VERSION 5.7 ;
  NOWIREEXTENSIONATPIN ON ;
  DIVIDERCHAR "/" ;
  BUSBITCHARS "[]" ;
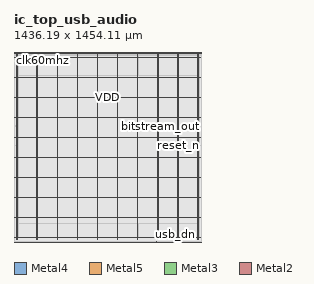
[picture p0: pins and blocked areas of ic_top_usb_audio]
MACRO ic_top_usb_audio
  CLASS BLOCK ;
  FOREIGN ic_top_usb_audio ;
  ORIGIN 0.000 0.000 ;
  SIZE 1436.190 BY 1454.110 ;
  PIN VDD
    DIRECTION INOUT ;
    USE POWER ;
    PORT
      LAYER Metal4 ;
        RECT 22.240 15.380 23.840 1435.020 ;
    END
    PORT
      LAYER Metal4 ;
        RECT 175.840 15.380 177.440 1435.020 ;
    END
    PORT
      LAYER Metal4 ;
        RECT 329.440 15.380 331.040 1435.020 ;
    END
    PORT
      LAYER Metal4 ;
        RECT 483.040 15.380 484.640 1435.020 ;
    END
    PORT
      LAYER Metal4 ;
        RECT 636.640 15.380 638.240 1435.020 ;
    END
    PORT
      LAYER Metal4 ;
        RECT 790.240 15.380 791.840 1435.020 ;
    END
    PORT
      LAYER Metal4 ;
        RECT 943.840 15.380 945.440 1435.020 ;
    END
    PORT
      LAYER Metal4 ;
        RECT 1097.440 15.380 1099.040 1435.020 ;
    END
    PORT
      LAYER Metal4 ;
        RECT 1251.040 15.380 1252.640 1435.020 ;
    END
    PORT
      LAYER Metal4 ;
        RECT 1404.640 15.380 1406.240 1435.020 ;
    END
    PORT
      LAYER Metal5 ;
        RECT 6.720 31.530 1429.120 33.130 ;
    END
    PORT
      LAYER Metal5 ;
        RECT 6.720 184.710 1429.120 186.310 ;
    END
    PORT
      LAYER Metal5 ;
        RECT 6.720 337.890 1429.120 339.490 ;
    END
    PORT
      LAYER Metal5 ;
        RECT 6.720 491.070 1429.120 492.670 ;
    END
    PORT
      LAYER Metal5 ;
        RECT 6.720 644.250 1429.120 645.850 ;
    END
    PORT
      LAYER Metal5 ;
        RECT 6.720 797.430 1429.120 799.030 ;
    END
    PORT
      LAYER Metal5 ;
        RECT 6.720 950.610 1429.120 952.210 ;
    END
    PORT
      LAYER Metal5 ;
        RECT 6.720 1103.790 1429.120 1105.390 ;
    END
    PORT
      LAYER Metal5 ;
        RECT 6.720 1256.970 1429.120 1258.570 ;
    END
    PORT
      LAYER Metal5 ;
        RECT 6.720 1410.150 1429.120 1411.750 ;
    END
  END VDD
  PIN VSS
    DIRECTION INOUT ;
    USE GROUND ;
    PORT
      LAYER Metal4 ;
        RECT 25.540 15.380 27.140 1435.020 ;
    END
    PORT
      LAYER Metal4 ;
        RECT 179.140 15.380 180.740 1435.020 ;
    END
    PORT
      LAYER Metal4 ;
        RECT 332.740 15.380 334.340 1435.020 ;
    END
    PORT
      LAYER Metal4 ;
        RECT 486.340 15.380 487.940 1435.020 ;
    END
    PORT
      LAYER Metal4 ;
        RECT 639.940 15.380 641.540 1435.020 ;
    END
    PORT
      LAYER Metal4 ;
        RECT 793.540 15.380 795.140 1435.020 ;
    END
    PORT
      LAYER Metal4 ;
        RECT 947.140 15.380 948.740 1435.020 ;
    END
    PORT
      LAYER Metal4 ;
        RECT 1100.740 15.380 1102.340 1435.020 ;
    END
    PORT
      LAYER Metal4 ;
        RECT 1254.340 15.380 1255.940 1435.020 ;
    END
    PORT
      LAYER Metal4 ;
        RECT 1407.940 15.380 1409.540 1435.020 ;
    END
    PORT
      LAYER Metal5 ;
        RECT 6.720 34.830 1429.120 36.430 ;
    END
    PORT
      LAYER Metal5 ;
        RECT 6.720 188.010 1429.120 189.610 ;
    END
    PORT
      LAYER Metal5 ;
        RECT 6.720 341.190 1429.120 342.790 ;
    END
    PORT
      LAYER Metal5 ;
        RECT 6.720 494.370 1429.120 495.970 ;
    END
    PORT
      LAYER Metal5 ;
        RECT 6.720 647.550 1429.120 649.150 ;
    END
    PORT
      LAYER Metal5 ;
        RECT 6.720 800.730 1429.120 802.330 ;
    END
    PORT
      LAYER Metal5 ;
        RECT 6.720 953.910 1429.120 955.510 ;
    END
    PORT
      LAYER Metal5 ;
        RECT 6.720 1107.090 1429.120 1108.690 ;
    END
    PORT
      LAYER Metal5 ;
        RECT 6.720 1260.270 1429.120 1261.870 ;
    END
    PORT
      LAYER Metal5 ;
        RECT 6.720 1413.450 1429.120 1415.050 ;
    END
  END VSS
  PIN bitstream_out
    DIRECTION OUTPUT ;
    USE SIGNAL ;
    ANTENNADIFFAREA 0.897600 ;
    PORT
      LAYER Metal3 ;
        RECT 1435.630 887.040 1436.190 887.600 ;
    END
  END bitstream_out
  PIN clk60mhz
    DIRECTION INPUT ;
    USE SIGNAL ;
    ANTENNAGATEAREA 0.396000 ;
    PORT
      LAYER Metal3 ;
        RECT 0.000 1425.760 0.560 1426.320 ;
    END
  END clk60mhz
  PIN reset_n
    DIRECTION INPUT ;
    USE SIGNAL ;
    ANTENNAGATEAREA 0.396000 ;
    PORT
      LAYER Metal3 ;
        RECT 1435.630 738.080 1436.190 738.640 ;
    END
  END reset_n
  PIN usb_dn
    DIRECTION INOUT ;
    USE SIGNAL ;
    ANTENNADIFFAREA 2.080400 ;
    PORT
      LAYER Metal2 ;
        RECT 1232.000 0.000 1232.560 0.560 ;
    END
  END usb_dn
  PIN usb_dp
    DIRECTION INOUT ;
    USE SIGNAL ;
    ANTENNADIFFAREA 2.080400 ;
    PORT
      LAYER Metal2 ;
        RECT 1223.040 0.000 1223.600 0.560 ;
    END
  END usb_dp
  PIN usb_dp_pull
    DIRECTION OUTPUT ;
    USE SIGNAL ;
    ANTENNADIFFAREA 0.897600 ;
    PORT
      LAYER Metal2 ;
        RECT 1088.640 0.000 1089.200 0.560 ;
    END
  END usb_dp_pull
  OBS
      LAYER Nwell ;
        RECT 6.290 15.250 1429.550 1435.150 ;
      LAYER Metal1 ;
        RECT 6.720 15.380 1429.120 1435.020 ;
      LAYER Metal2 ;
        RECT 9.100 0.860 1427.300 1434.910 ;
        RECT 9.100 0.090 1088.340 0.860 ;
        RECT 1089.500 0.090 1222.740 0.860 ;
        RECT 1223.900 0.090 1231.700 0.860 ;
        RECT 1232.860 0.090 1427.300 0.860 ;
      LAYER Metal3 ;
        RECT 0.560 1426.620 1435.630 1434.860 ;
        RECT 0.860 1425.460 1435.630 1426.620 ;
        RECT 0.560 887.900 1435.630 1425.460 ;
        RECT 0.560 886.740 1435.330 887.900 ;
        RECT 0.560 738.940 1435.630 886.740 ;
        RECT 0.560 737.780 1435.330 738.940 ;
        RECT 0.560 0.140 1435.630 737.780 ;
      LAYER Metal4 ;
        RECT 33.180 37.050 175.540 1429.030 ;
        RECT 177.740 37.050 178.840 1429.030 ;
        RECT 181.040 37.050 329.140 1429.030 ;
        RECT 331.340 37.050 332.440 1429.030 ;
        RECT 334.640 37.050 482.740 1429.030 ;
        RECT 484.940 37.050 486.040 1429.030 ;
        RECT 488.240 37.050 636.340 1429.030 ;
        RECT 638.540 37.050 639.640 1429.030 ;
        RECT 641.840 37.050 789.940 1429.030 ;
        RECT 792.140 37.050 793.240 1429.030 ;
        RECT 795.440 37.050 943.540 1429.030 ;
        RECT 945.740 37.050 946.840 1429.030 ;
        RECT 949.040 37.050 1097.140 1429.030 ;
        RECT 1099.340 37.050 1100.440 1429.030 ;
        RECT 1102.640 37.050 1250.740 1429.030 ;
        RECT 1252.940 37.050 1254.040 1429.030 ;
        RECT 1256.240 37.050 1404.340 1429.030 ;
        RECT 1406.540 37.050 1407.640 1429.030 ;
        RECT 1409.840 37.050 1420.020 1429.030 ;
      LAYER Metal5 ;
        RECT 33.100 1262.470 1420.100 1276.870 ;
        RECT 33.100 1259.170 1420.100 1259.670 ;
        RECT 33.100 1109.290 1420.100 1256.370 ;
        RECT 33.100 1105.990 1420.100 1106.490 ;
        RECT 33.100 956.110 1420.100 1103.190 ;
        RECT 33.100 952.810 1420.100 953.310 ;
        RECT 33.100 802.930 1420.100 950.010 ;
        RECT 33.100 799.630 1420.100 800.130 ;
        RECT 33.100 649.750 1420.100 796.830 ;
        RECT 33.100 646.450 1420.100 646.950 ;
        RECT 33.100 496.570 1420.100 643.650 ;
        RECT 33.100 493.270 1420.100 493.770 ;
        RECT 33.100 343.390 1420.100 490.470 ;
        RECT 33.100 340.090 1420.100 340.590 ;
        RECT 33.100 190.210 1420.100 337.290 ;
        RECT 33.100 186.910 1420.100 187.410 ;
        RECT 33.100 141.530 1420.100 184.110 ;
  END
END ic_top_usb_audio
END LIBRARY

